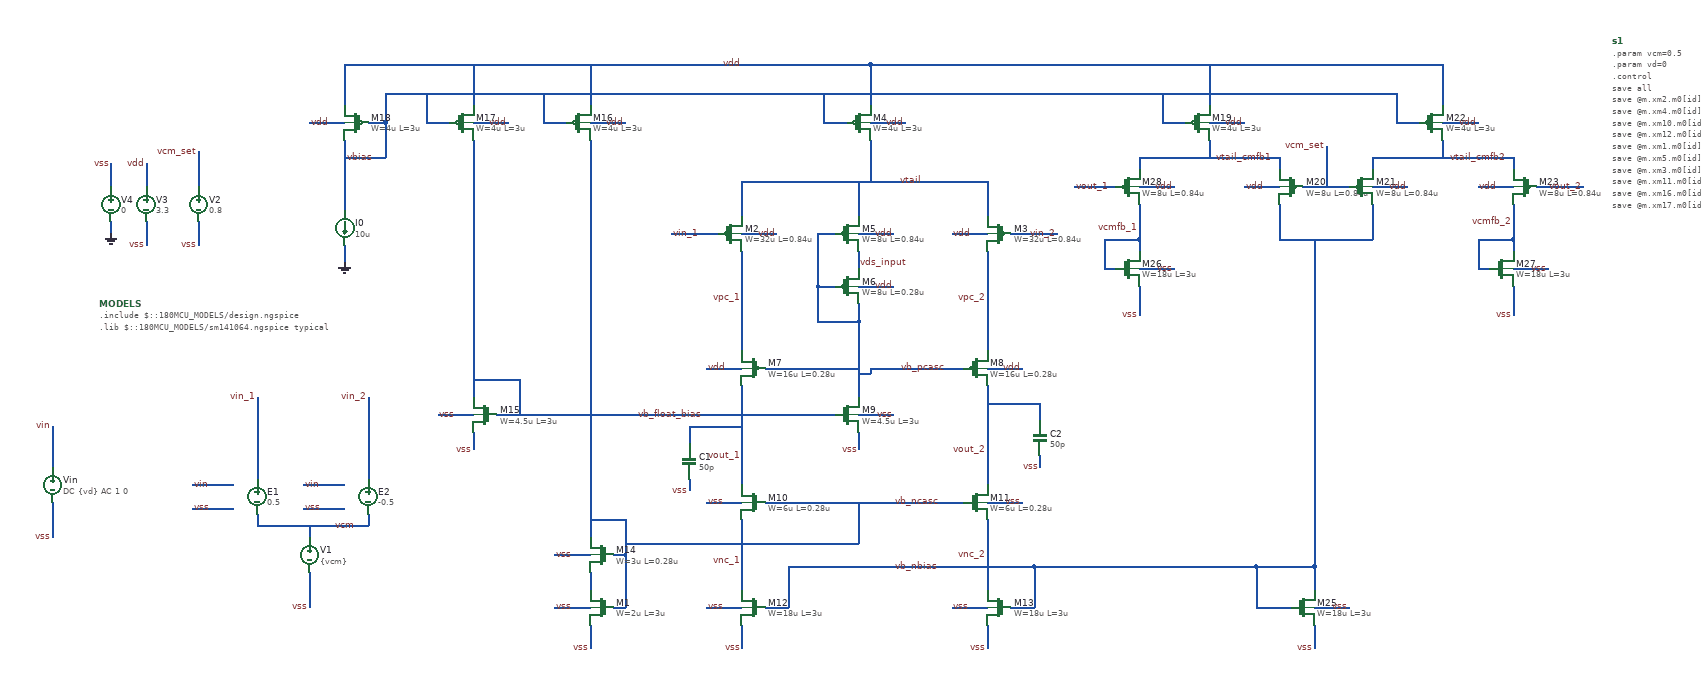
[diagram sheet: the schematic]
v {xschem version=3.4.8RC file_version=1.3}
G {}
K {}
V {}
S {}
F {}
E {}
N -100 -1020 -100 -950 {lab=vdd}
N -100 -1020 780 -1020 {lab=vdd}
N 320 -1020 320 -950 {lab=vdd}
N 120 -1020 120 -950 {lab=vdd}
N 580 -820 580 -760 {lab=vtail}
N 580 -820 1000 -820 {lab=vtail}
N 1000 -820 1000 -760 {lab=vtail}
N 780 -1020 800 -1020 {lab=vdd}
N 800 -1020 800 -950 {lab=vdd}
N 800 -890 800 -820 {lab=vtail}
N 780 -820 780 -760 {lab=vtail}
N 710 -730 740 -730 {lab=vb_pcasc}
N 710 -730 710 -640 {lab=vb_pcasc}
N 710 -640 740 -640 {lab=vb_pcasc}
N 710 -640 710 -580 {lab=vb_pcasc}
N 710 -580 780 -580 {lab=vb_pcasc}
N 780 -610 780 -580 {lab=vb_pcasc}
N 780 -700 780 -670 {lab=vds_input}
N 780 -580 780 -450 {lab=vb_pcasc}
N 620 -500 780 -500 {lab=vb_pcasc}
N 780 -490 800 -490 {lab=vb_pcasc}
N 800 -500 800 -490 {lab=vb_pcasc}
N 800 -500 960 -500 {lab=vb_pcasc}
N 780 -390 780 -360 {lab=vss}
N 120 -390 120 -360 {lab=vss}
N 160 -420 740 -420 {lab=vb_float_bias}
N 120 -890 120 -450 {lab=vb_float_bias}
N 200 -480 200 -420 {lab=vb_float_bias}
N 120 -480 200 -480 {lab=vb_float_bias}
N -100 -890 -100 -770 {lab=vbias}
N -60 -920 -30 -920 {lab=vbias}
N -30 -920 -30 -860 {lab=vbias}
N -100 -860 -30 -860 {lab=vbias}
N 320 -890 320 -210 {lab=vb_ncasc}
N 360 -90 380 -90 {lab=vb_ncasc}
N 380 -180 380 -90 {lab=vb_ncasc}
N 360 -180 380 -180 {lab=vb_ncasc}
N 380 -240 380 -180 {lab=vb_ncasc}
N 320 -240 380 -240 {lab=vb_ncasc}
N 320 -150 320 -120 {lab=#net1}
N 320 -60 320 -20 {lab=vss}
N 580 -700 580 -530 {lab=vpc_1}
N 580 -240 580 -120 {lab=vnc_1}
N 580 -470 580 -300 {lab=vout_1}
N 1000 -470 1000 -300 {lab=vout_2}
N 1000 -240 1000 -120 {lab=vnc_2}
N 620 -270 960 -270 {lab=vb_ncasc}
N 380 -200 780 -200 {lab=vb_ncasc}
N 780 -270 780 -200 {lab=vb_ncasc}
N 1000 -700 1000 -530 {lab=vpc_2}
N 580 -60 580 -20 {lab=vss}
N 1000 -60 1000 -20 {lab=vss}
N 1540 -810 1620 -810 {lab=vcm_set}
N 1660 -780 1660 -720 {lab=vb_nbias}
N 1500 -720 1660 -720 {lab=vb_nbias}
N 1500 -780 1500 -720 {lab=vb_nbias}
N 1460 -160 1460 -90 {lab=vb_nbias}
N 1460 -160 1560 -160 {lab=vb_nbias}
N 1560 -160 1560 -120 {lab=vb_nbias}
N 1560 -720 1560 -160 {lab=vb_nbias}
N 1500 -860 1500 -840 {lab=vtail_cmfb1}
N 1260 -860 1260 -840 {lab=vtail_cmfb1}
N 1260 -860 1490 -860 {lab=vtail_cmfb1}
N 1490 -860 1500 -860 {lab=vtail_cmfb1}
N 1380 -890 1380 -860 {lab=vtail_cmfb1}
N 800 -1020 1780 -1020 {lab=vdd}
N 1780 -1020 1780 -950 {lab=vdd}
N 1660 -860 1660 -840 {lab=vtail_cmfb2}
N 1660 -860 1900 -860 {lab=vtail_cmfb2}
N 1900 -860 1900 -840 {lab=vtail_cmfb2}
N 1780 -890 1780 -860 {lab=vtail_cmfb2}
N 1560 -60 1560 -20 {lab=vss}
N 1200 -670 1220 -670 {lab=vcmfb_1}
N 1200 -720 1200 -670 {lab=vcmfb_1}
N 1200 -720 1260 -720 {lab=vcmfb_1}
N 1260 -720 1260 -700 {lab=vcmfb_1}
N 1260 -780 1260 -720 {lab=vcmfb_1}
N 1260 -640 1260 -590 {lab=vss}
N 1840 -670 1860 -670 {lab=vcmfb_2}
N 1840 -720 1840 -670 {lab=vcmfb_2}
N 1840 -720 1900 -720 {lab=vcmfb_2}
N 1900 -720 1900 -700 {lab=vcmfb_2}
N 1900 -780 1900 -720 {lab=vcmfb_2}
N 1900 -640 1900 -590 {lab=vss}
N 460 -730 540 -730 {lab=vin_1}
N 1040 -730 1120 -730 {lab=vin_2}
N 1380 -1020 1380 -950 {lab=vdd}
N -30 -970 -30 -920 {lab=vbias}
N -30 -970 1700 -970 {lab=vbias}
N 1700 -920 1740 -920 {lab=vbias}
N 1700 -970 1700 -920 {lab=vbias}
N 1300 -920 1340 -920 {lab=vbias}
N 1300 -970 1300 -920 {lab=vbias}
N 720 -920 760 -920 {lab=vbias}
N 720 -970 720 -920 {lab=vbias}
N 240 -920 280 -920 {lab=vbias}
N 240 -970 240 -920 {lab=vbias}
N 40 -920 80 -920 {lab=vbias}
N 40 -970 40 -920 {lab=vbias}
N -100 -710 -100 -680 {lab=0}
N 1180 -810 1220 -810 {lab=vout_2}
N 1940 -810 1980 -810 {lab=vout_2}
N -160 -920 -100 -920 {lab=vdd}
N 120 -920 180 -920 {lab=vdd}
N 320 -920 380 -920 {lab=vdd}
N 800 -920 860 -920 {lab=vdd}
N 1380 -920 1440 -920 {lab=vdd}
N 1780 -920 1840 -920 {lab=vdd}
N 1660 -810 1720 -810 {lab=vdd}
N 1440 -810 1500 -810 {lab=vdd}
N 1260 -810 1320 -810 {lab=vdd}
N 1840 -810 1900 -810 {lab=vdd}
N 580 -730 640 -730 {lab=vdd}
N 940 -730 1000 -730 {lab=vdd}
N 780 -730 840 -730 {lab=vdd}
N 780 -640 840 -640 {lab=vdd}
N 520 -500 580 -500 {lab=vdd}
N 1000 -500 1060 -500 {lab=vdd}
N 780 -420 840 -420 {lab=vss}
N 520 -270 580 -270 {lab=vss}
N 1000 -270 1060 -270 {lab=vss}
N 940 -90 1000 -90 {lab=vss}
N 520 -90 580 -90 {lab=vss}
N 260 -90 320 -90 {lab=vss}
N 260 -180 320 -180 {lab=vss}
N 60 -420 120 -420 {lab=vss}
N 1460 -90 1520 -90 {lab=vb_nbias}
N 1080 -160 1460 -160 {lab=vb_nbias}
N 1080 -160 1080 -90 {lab=vb_nbias}
N 1040 -90 1080 -90 {lab=vb_nbias}
N 660 -160 1080 -160 {lab=vb_nbias}
N 660 -160 660 -90 {lab=vb_nbias}
N 620 -90 660 -90 {lab=vb_nbias}
N 1150 -810 1180 -810 {lab=vout_2}
N 1980 -810 2020 -810 {lab=vout_2}
N 1580 -880 1580 -810 {lab=vcm_set}
N -500 -750 -500 -730 {lab=0}
N -500 -850 -500 -820 {lab=vss}
N -500 -820 -500 -810 {lab=vss}
N -440 -750 -440 -730 {lab=vss}
N -440 -730 -440 -710 {lab=vss}
N -440 -850 -440 -810 {lab=vdd}
N -250 -250 -250 -230 {lab=vcm}
N -140 -230 -60 -230 {lab=vcm}
N -60 -250 -60 -230 {lab=vcm}
N -160 -230 -160 -210 {lab=vcm}
N -160 -150 -160 -90 {lab=vss}
N -250 -450 -250 -310 {lab=vin_1}
N -60 -360 -60 -310 {lab=vin_2}
N -250 -230 -140 -230 {lab=vcm}
N -360 -260 -290 -260 {lab=vss}
N -360 -300 -290 -300 {lab=vin}
N -170 -260 -100 -260 {lab=vss}
N -170 -300 -100 -300 {lab=vin}
N -600 -270 -600 -210 {lab=vss}
N -600 -400 -600 -330 {lab=vin}
N -60 -450 -60 -360 {lab=vin_2}
N -350 -750 -350 -730 {lab=vss}
N -350 -730 -350 -710 {lab=vss}
N -350 -850 -350 -810 {lab=vcm_set}
N -350 -870 -350 -850 {lab=vcm_set}
N 1260 -670 1320 -670 {lab=vss}
N 1900 -670 1960 -670 {lab=vss}
N 1560 -90 1620 -90 {lab=vss}
N 490 -400 490 -370 {lab=vout_1}
N 490 -400 580 -400 {lab=vout_1}
N 490 -310 490 -290 {lab=vss}
N 1090 -440 1090 -410 {lab=vout_2}
N 1000 -440 1090 -440 {lab=vout_2}
N 1090 -350 1090 -330 {lab=vss}
C {symbols/pfet_03v3.sym} 560 -730 0 0 {name=M2
L=0.84u
W=32u
nf=8
m=1
ad="'int((nf+1)/2) * W/nf * 0.18u'"
pd="'2*int((nf+1)/2) * (W/nf + 0.18u)'"
as="'int((nf+2)/2) * W/nf * 0.18u'"
ps="'2*int((nf+2)/2) * (W/nf + 0.18u)'"
nrd="'0.18u / W'" nrs="'0.18u / W'"
sa=0 sb=0 sd=0
model=pfet_03v3
spiceprefix=X
}
C {symbols/pfet_03v3.sym} 780 -920 0 0 {name=M4
L=3u
W=4u
nf=1
m=50
ad="'int((nf+1)/2) * W/nf * 0.18u'"
pd="'2*int((nf+1)/2) * (W/nf + 0.18u)'"
as="'int((nf+2)/2) * W/nf * 0.18u'"
ps="'2*int((nf+2)/2) * (W/nf + 0.18u)'"
nrd="'0.18u / W'" nrs="'0.18u / W'"
sa=0 sb=0 sd=0
model=pfet_03v3
spiceprefix=X
}
C {symbols/nfet_03v3.sym} 600 -270 0 1 {name=M10
L=0.28u
W=6u
nf=2
m=1
ad="'int((nf+1)/2) * W/nf * 0.18u'"
pd="'2*int((nf+1)/2) * (W/nf + 0.18u)'"
as="'int((nf+2)/2) * W/nf * 0.18u'"
ps="'2*int((nf+2)/2) * (W/nf + 0.18u)'"
nrd="'0.18u / W'" nrs="'0.18u / W'"
sa=0 sb=0 sd=0
model=nfet_03v3
spiceprefix=X
}
C {symbols/nfet_03v3.sym} 600 -90 0 1 {name=M12
L=3u
W=18u
nf=4
m=1
ad="'int((nf+1)/2) * W/nf * 0.18u'"
pd="'2*int((nf+1)/2) * (W/nf + 0.18u)'"
as="'int((nf+2)/2) * W/nf * 0.18u'"
ps="'2*int((nf+2)/2) * (W/nf + 0.18u)'"
nrd="'0.18u / W'" nrs="'0.18u / W'"
sa=0 sb=0 sd=0
model=nfet_03v3
spiceprefix=X
}
C {symbols/nfet_03v3.sym} 340 -90 0 1 {name=M1
L=3u
W=2u
nf=1
m=1
ad="'int((nf+1)/2) * W/nf * 0.18u'"
pd="'2*int((nf+1)/2) * (W/nf + 0.18u)'"
as="'int((nf+2)/2) * W/nf * 0.18u'"
ps="'2*int((nf+2)/2) * (W/nf + 0.18u)'"
nrd="'0.18u / W'" nrs="'0.18u / W'"
sa=0 sb=0 sd=0
model=nfet_03v3
spiceprefix=X
}
C {symbols/pfet_03v3.sym} 760 -730 0 0 {name=M5
L=0.84u
W=8u
nf=2
m=1
ad="'int((nf+1)/2) * W/nf * 0.18u'"
pd="'2*int((nf+1)/2) * (W/nf + 0.18u)'"
as="'int((nf+2)/2) * W/nf * 0.18u'"
ps="'2*int((nf+2)/2) * (W/nf + 0.18u)'"
nrd="'0.18u / W'" nrs="'0.18u / W'"
sa=0 sb=0 sd=0
model=pfet_03v3
spiceprefix=X
}
C {isource.sym} -100 -740 0 0 {name=I0 value=10u}
C {symbols/pfet_03v3.sym} 1020 -730 0 1 {name=M3
L=0.84u
W=32u
nf=8
m=1
ad="'int((nf+1)/2) * W/nf * 0.18u'"
pd="'2*int((nf+1)/2) * (W/nf + 0.18u)'"
as="'int((nf+2)/2) * W/nf * 0.18u'"
ps="'2*int((nf+2)/2) * (W/nf + 0.18u)'"
nrd="'0.18u / W'" nrs="'0.18u / W'"
sa=0 sb=0 sd=0
model=pfet_03v3
spiceprefix=X
}
C {symbols/nfet_03v3.sym} 980 -270 0 0 {name=M11
L=0.28u
W=6u
nf=2
m=1
ad="'int((nf+1)/2) * W/nf * 0.18u'"
pd="'2*int((nf+1)/2) * (W/nf + 0.18u)'"
as="'int((nf+2)/2) * W/nf * 0.18u'"
ps="'2*int((nf+2)/2) * (W/nf + 0.18u)'"
nrd="'0.18u / W'" nrs="'0.18u / W'"
sa=0 sb=0 sd=0
model=nfet_03v3
spiceprefix=X
}
C {symbols/pfet_03v3.sym} 300 -920 0 0 {name=M16
L=3u
W=4u
nf=1
m=10
ad="'int((nf+1)/2) * W/nf * 0.18u'"
pd="'2*int((nf+1)/2) * (W/nf + 0.18u)'"
as="'int((nf+2)/2) * W/nf * 0.18u'"
ps="'2*int((nf+2)/2) * (W/nf + 0.18u)'"
nrd="'0.18u / W'" nrs="'0.18u / W'"
sa=0 sb=0 sd=0
model=pfet_03v3
spiceprefix=X
}
C {symbols/pfet_03v3.sym} 100 -920 0 0 {name=M17
L=3u
W=4u
nf=1
m=10
ad="'int((nf+1)/2) * W/nf * 0.18u'"
pd="'2*int((nf+1)/2) * (W/nf + 0.18u)'"
as="'int((nf+2)/2) * W/nf * 0.18u'"
ps="'2*int((nf+2)/2) * (W/nf + 0.18u)'"
nrd="'0.18u / W'" nrs="'0.18u / W'"
sa=0 sb=0 sd=0
model=pfet_03v3
spiceprefix=X
}
C {symbols/pfet_03v3.sym} -80 -920 0 1 {name=M18
L=3u
W=4u
nf=1
m=10
ad="'int((nf+1)/2) * W/nf * 0.18u'"
pd="'2*int((nf+1)/2) * (W/nf + 0.18u)'"
as="'int((nf+2)/2) * W/nf * 0.18u'"
ps="'2*int((nf+2)/2) * (W/nf + 0.18u)'"
nrd="'0.18u / W'" nrs="'0.18u / W'"
sa=0 sb=0 sd=0
model=pfet_03v3
spiceprefix=X
}
C {symbols/nfet_03v3.sym} 1020 -90 0 1 {name=M13
L=3u
W=18u
nf=4
m=1
ad="'int((nf+1)/2) * W/nf * 0.18u'"
pd="'2*int((nf+1)/2) * (W/nf + 0.18u)'"
as="'int((nf+2)/2) * W/nf * 0.18u'"
ps="'2*int((nf+2)/2) * (W/nf + 0.18u)'"
nrd="'0.18u / W'" nrs="'0.18u / W'"
sa=0 sb=0 sd=0
model=nfet_03v3
spiceprefix=X
}
C {symbols/nfet_03v3.sym} 140 -420 0 1 {name=M15
L=3u
W=4.5u
nf=1
m=1
ad="'int((nf+1)/2) * W/nf * 0.18u'"
pd="'2*int((nf+1)/2) * (W/nf + 0.18u)'"
as="'int((nf+2)/2) * W/nf * 0.18u'"
ps="'2*int((nf+2)/2) * (W/nf + 0.18u)'"
nrd="'0.18u / W'" nrs="'0.18u / W'"
sa=0 sb=0 sd=0
model=nfet_03v3
spiceprefix=X
}
C {symbols/nfet_03v3.sym} 760 -420 0 0 {name=M9
L=3u
W=4.5u
nf=1
m=1
ad="'int((nf+1)/2) * W/nf * 0.18u'"
pd="'2*int((nf+1)/2) * (W/nf + 0.18u)'"
as="'int((nf+2)/2) * W/nf * 0.18u'"
ps="'2*int((nf+2)/2) * (W/nf + 0.18u)'"
nrd="'0.18u / W'" nrs="'0.18u / W'"
sa=0 sb=0 sd=0
model=nfet_03v3
spiceprefix=X
}
C {symbols/pfet_03v3.sym} 1360 -920 0 0 {name=M19
L=3u
W=4u
nf=1
m=20
ad="'int((nf+1)/2) * W/nf * 0.18u'"
pd="'2*int((nf+1)/2) * (W/nf + 0.18u)'"
as="'int((nf+2)/2) * W/nf * 0.18u'"
ps="'2*int((nf+2)/2) * (W/nf + 0.18u)'"
nrd="'0.18u / W'" nrs="'0.18u / W'"
sa=0 sb=0 sd=0
model=pfet_03v3
spiceprefix=X
}
C {symbols/pfet_03v3.sym} 1760 -920 0 0 {name=M22
L=3u
W=4u
nf=1
m=20
ad="'int((nf+1)/2) * W/nf * 0.18u'"
pd="'2*int((nf+1)/2) * (W/nf + 0.18u)'"
as="'int((nf+2)/2) * W/nf * 0.18u'"
ps="'2*int((nf+2)/2) * (W/nf + 0.18u)'"
nrd="'0.18u / W'" nrs="'0.18u / W'"
sa=0 sb=0 sd=0
model=pfet_03v3
spiceprefix=X
}
C {symbols/nfet_03v3.sym} 1540 -90 0 0 {name=M25
L=3u
W=18u
nf=4
m=1
ad="'int((nf+1)/2) * W/nf * 0.18u'"
pd="'2*int((nf+1)/2) * (W/nf + 0.18u)'"
as="'int((nf+2)/2) * W/nf * 0.18u'"
ps="'2*int((nf+2)/2) * (W/nf + 0.18u)'"
nrd="'0.18u / W'" nrs="'0.18u / W'"
sa=0 sb=0 sd=0
model=nfet_03v3
spiceprefix=X
}
C {symbols/nfet_03v3.sym} 1240 -670 0 0 {name=M26
L=3u
W=18u
nf=2
m=1
ad="'int((nf+1)/2) * W/nf * 0.18u'"
pd="'2*int((nf+1)/2) * (W/nf + 0.18u)'"
as="'int((nf+2)/2) * W/nf * 0.18u'"
ps="'2*int((nf+2)/2) * (W/nf + 0.18u)'"
nrd="'0.18u / W'" nrs="'0.18u / W'"
sa=0 sb=0 sd=0
model=nfet_03v3
spiceprefix=X
}
C {symbols/nfet_03v3.sym} 1880 -670 0 0 {name=M27
L=3u
W=18u
nf=2
m=1
ad="'int((nf+1)/2) * W/nf * 0.18u'"
pd="'2*int((nf+1)/2) * (W/nf + 0.18u)'"
as="'int((nf+2)/2) * W/nf * 0.18u'"
ps="'2*int((nf+2)/2) * (W/nf + 0.18u)'"
nrd="'0.18u / W'" nrs="'0.18u / W'"
sa=0 sb=0 sd=0
model=nfet_03v3
spiceprefix=X
}
C {symbols/pfet_03v3.sym} 1240 -810 0 0 {name=M28
L=0.84u
W=8u
nf=2
m=1
ad="'int((nf+1)/2) * W/nf * 0.18u'"
pd="'2*int((nf+1)/2) * (W/nf + 0.18u)'"
as="'int((nf+2)/2) * W/nf * 0.18u'"
ps="'2*int((nf+2)/2) * (W/nf + 0.18u)'"
nrd="'0.18u / W'" nrs="'0.18u / W'"
sa=0 sb=0 sd=0
model=pfet_03v3
spiceprefix=X
}
C {symbols/pfet_03v3.sym} 1520 -810 0 1 {name=M20
L=0.84u
W=8u
nf=2
m=1
ad="'int((nf+1)/2) * W/nf * 0.18u'"
pd="'2*int((nf+1)/2) * (W/nf + 0.18u)'"
as="'int((nf+2)/2) * W/nf * 0.18u'"
ps="'2*int((nf+2)/2) * (W/nf + 0.18u)'"
nrd="'0.18u / W'" nrs="'0.18u / W'"
sa=0 sb=0 sd=0
model=pfet_03v3
spiceprefix=X
}
C {symbols/pfet_03v3.sym} 1640 -810 0 0 {name=M21
L=0.84u
W=8u
nf=2
m=1
ad="'int((nf+1)/2) * W/nf * 0.18u'"
pd="'2*int((nf+1)/2) * (W/nf + 0.18u)'"
as="'int((nf+2)/2) * W/nf * 0.18u'"
ps="'2*int((nf+2)/2) * (W/nf + 0.18u)'"
nrd="'0.18u / W'" nrs="'0.18u / W'"
sa=0 sb=0 sd=0
model=pfet_03v3
spiceprefix=X
}
C {symbols/pfet_03v3.sym} 1920 -810 0 1 {name=M23
L=0.84u
W=8u
nf=2
m=1
ad="'int((nf+1)/2) * W/nf * 0.18u'"
pd="'2*int((nf+1)/2) * (W/nf + 0.18u)'"
as="'int((nf+2)/2) * W/nf * 0.18u'"
ps="'2*int((nf+2)/2) * (W/nf + 0.18u)'"
nrd="'0.18u / W'" nrs="'0.18u / W'"
sa=0 sb=0 sd=0
model=pfet_03v3
spiceprefix=X
}
C {lab_wire.sym} -160 -920 0 1 {name=p1 sig_type=std_logic lab=vdd}
C {lab_wire.sym} 180 -920 0 0 {name=p2 sig_type=std_logic lab=vdd}
C {lab_wire.sym} 380 -920 0 0 {name=p3 sig_type=std_logic lab=vdd}
C {lab_wire.sym} 860 -920 0 0 {name=p4 sig_type=std_logic lab=vdd}
C {lab_wire.sym} 1440 -920 0 0 {name=p5 sig_type=std_logic lab=vdd}
C {lab_wire.sym} 1840 -920 0 0 {name=p6 sig_type=std_logic lab=vdd}
C {lab_wire.sym} 1720 -810 0 0 {name=p7 sig_type=std_logic lab=vdd}
C {lab_wire.sym} 1440 -810 0 1 {name=p8 sig_type=std_logic lab=vdd}
C {lab_wire.sym} 1320 -810 0 0 {name=p9 sig_type=std_logic lab=vdd}
C {lab_wire.sym} 1840 -810 0 1 {name=p10 sig_type=std_logic lab=vdd}
C {lab_wire.sym} 640 -730 0 0 {name=p11 sig_type=std_logic lab=vdd}
C {lab_wire.sym} 940 -730 0 1 {name=p12 sig_type=std_logic lab=vdd}
C {lab_wire.sym} 840 -730 0 0 {name=p13 sig_type=std_logic lab=vdd}
C {lab_wire.sym} 840 -640 0 0 {name=p14 sig_type=std_logic lab=vdd}
C {symbols/pfet_03v3.sym} 760 -640 0 0 {name=M6
L=0.28u
W=8u
nf=2
m=1
ad="'int((nf+1)/2) * W/nf * 0.18u'"
pd="'2*int((nf+1)/2) * (W/nf + 0.18u)'"
as="'int((nf+2)/2) * W/nf * 0.18u'"
ps="'2*int((nf+2)/2) * (W/nf + 0.18u)'"
nrd="'0.18u / W'" nrs="'0.18u / W'"
sa=0 sb=0 sd=0
model=pfet_03v3
spiceprefix=X
}
C {symbols/pfet_03v3.sym} 600 -500 0 1 {name=M7
L=0.28u
W=16u
nf=4
m=1
ad="'int((nf+1)/2) * W/nf * 0.18u'"
pd="'2*int((nf+1)/2) * (W/nf + 0.18u)'"
as="'int((nf+2)/2) * W/nf * 0.18u'"
ps="'2*int((nf+2)/2) * (W/nf + 0.18u)'"
nrd="'0.18u / W'" nrs="'0.18u / W'"
sa=0 sb=0 sd=0
model=pfet_03v3
spiceprefix=X
}
C {symbols/pfet_03v3.sym} 980 -500 0 0 {name=M8
L=0.28u
W=16u
nf=4
m=1
ad="'int((nf+1)/2) * W/nf * 0.18u'"
pd="'2*int((nf+1)/2) * (W/nf + 0.18u)'"
as="'int((nf+2)/2) * W/nf * 0.18u'"
ps="'2*int((nf+2)/2) * (W/nf + 0.18u)'"
nrd="'0.18u / W'" nrs="'0.18u / W'"
sa=0 sb=0 sd=0
model=pfet_03v3
spiceprefix=X
}
C {lab_wire.sym} 520 -500 0 1 {name=p15 sig_type=std_logic lab=vdd}
C {lab_wire.sym} 1060 -500 0 0 {name=p16 sig_type=std_logic lab=vdd}
C {lab_wire.sym} 840 -420 0 0 {name=p17 sig_type=std_logic lab=vss}
C {lab_wire.sym} 520 -270 0 1 {name=p18 sig_type=std_logic lab=vss}
C {lab_wire.sym} 1060 -270 0 0 {name=p19 sig_type=std_logic lab=vss}
C {lab_wire.sym} 940 -90 0 1 {name=p20 sig_type=std_logic lab=vss}
C {lab_wire.sym} 520 -90 0 1 {name=p21 sig_type=std_logic lab=vss}
C {lab_wire.sym} 260 -90 0 1 {name=p22 sig_type=std_logic lab=vss}
C {lab_wire.sym} 260 -180 0 1 {name=p23 sig_type=std_logic lab=vss}
C {lab_wire.sym} 60 -420 0 1 {name=p24 sig_type=std_logic lab=vss}
C {lab_wire.sym} 320 -20 3 1 {name=p25 sig_type=std_logic lab=vss}
C {lab_wire.sym} 580 -20 3 1 {name=p26 sig_type=std_logic lab=vss}
C {lab_wire.sym} 1000 -20 3 1 {name=p27 sig_type=std_logic lab=vss}
C {lab_wire.sym} 780 -360 3 1 {name=p28 sig_type=std_logic lab=vss}
C {lab_wire.sym} 120 -360 1 0 {name=p29 sig_type=std_logic lab=vss}
C {lab_wire.sym} 1560 -20 3 1 {name=p30 sig_type=std_logic lab=vss}
C {lab_wire.sym} 1260 -590 3 1 {name=p31 sig_type=std_logic lab=vss}
C {lab_wire.sym} 1900 -590 3 1 {name=p32 sig_type=std_logic lab=vss}
C {lab_wire.sym} 580 -1020 0 0 {name=p33 sig_type=std_logic lab=vdd}
C {symbols/nfet_03v3.sym} 340 -180 0 1 {name=M14
L=0.28u
W=3u
nf=1
m=1
ad="'int((nf+1)/2) * W/nf * 0.18u'"
pd="'2*int((nf+1)/2) * (W/nf + 0.18u)'"
as="'int((nf+2)/2) * W/nf * 0.18u'"
ps="'2*int((nf+2)/2) * (W/nf + 0.18u)'"
nrd="'0.18u / W'" nrs="'0.18u / W'"
sa=0 sb=0 sd=0
model=nfet_03v3
spiceprefix=X
}
C {lab_wire.sym} 460 -730 0 1 {name=p35 sig_type=std_logic lab=vin_1}
C {lab_wire.sym} 1120 -730 0 0 {name=p36 sig_type=std_logic lab=vin_2}
C {lab_wire.sym} 890 -820 0 0 {name=p37 sig_type=std_logic lab=vtail}
C {lab_wire.sym} 580 -620 1 0 {name=p38 sig_type=std_logic lab=vpc_1}
C {lab_wire.sym} 1000 -620 1 0 {name=p39 sig_type=std_logic lab=vpc_2}
C {lab_wire.sym} 850 -500 0 1 {name=p40 sig_type=std_logic lab=vb_pcasc}
C {lab_wire.sym} 840 -270 0 1 {name=p41 sig_type=std_logic lab=vb_ncasc}
C {lab_wire.sym} 840 -160 0 1 {name=p42 sig_type=std_logic lab=vb_nbias}
C {lab_wire.sym} 780 -680 0 1 {name=p43 sig_type=std_logic lab=vds_input}
C {lab_wire.sym} 400 -420 0 1 {name=p44 sig_type=std_logic lab=vb_float_bias}
C {lab_wire.sym} 580 -350 3 1 {name=p45 sig_type=std_logic lab=vout_1}
C {lab_wire.sym} 1000 -360 1 0 {name=p46 sig_type=std_logic lab=vout_2}
C {lab_wire.sym} 1150 -810 0 1 {name=p47 sig_type=std_logic lab=vout_1}
C {lab_wire.sym} 2020 -810 0 0 {name=p48 sig_type=std_logic lab=vout_2}
C {lab_wire.sym} 1490 -860 0 0 {name=p49 sig_type=std_logic lab=vtail_cmfb1}
C {lab_wire.sym} 1890 -860 0 0 {name=p50 sig_type=std_logic lab=vtail_cmfb2}
C {lab_wire.sym} 1580 -880 1 1 {name=p51 sig_type=std_logic lab=vcm_set}
C {lab_wire.sym} 1260 -740 0 0 {name=p52 sig_type=std_logic lab=vcmfb_1}
C {lab_wire.sym} 1900 -750 0 0 {name=p53 sig_type=std_logic lab=vcmfb_2}
C {lab_wire.sym} -50 -860 0 0 {name=p54 sig_type=std_logic lab=vbias}
C {vsource.sym} -440 -780 0 0 {name=V3 value=3.3 savecurrent=false}
C {vsource.sym} -500 -780 0 0 {name=V4 value=0 savecurrent=false}
C {gnd.sym} -500 -730 0 0 {name=l2 lab=0}
C {lab_wire.sym} -500 -850 3 0 {name=p55 sig_type=std_logic lab=vss}
C {lab_wire.sym} -440 -710 3 1 {name=p56 sig_type=std_logic lab=vss}
C {lab_wire.sym} -440 -850 3 0 {name=p57 sig_type=std_logic lab=vdd}
C {vsource.sym} -160 -180 0 0 {name=V1 value=\{vcm\} savecurrent=false}
C {lab_wire.sym} -160 -90 3 1 {name=p58 sig_type=std_logic lab=vss}
C {lab_wire.sym} -80 -230 0 0 {name=p59 sig_type=std_logic lab=vcm}
C {devices/code_shown.sym} -520 -610 0 0 {name=MODELS only_toplevel=true
format="tcleval( @value )"
value="
.include $::180MCU_MODELS/design.ngspice
.lib $::180MCU_MODELS/sm141064.ngspice typical
"}
C {vcvs.sym} -250 -280 0 0 {name=E1 value=0.5}
C {vcvs.sym} -60 -280 0 0 {name=E2 value=-0.5}
C {lab_wire.sym} -360 -260 0 1 {name=p60 sig_type=std_logic lab=vss}
C {lab_wire.sym} -360 -300 0 1 {name=p61 sig_type=std_logic lab=vin}
C {lab_wire.sym} -170 -260 0 1 {name=p62 sig_type=std_logic lab=vss}
C {lab_wire.sym} -170 -300 0 1 {name=p63 sig_type=std_logic lab=vin}
C {vsource.sym} -600 -300 0 0 {name=Vin value="DC \{vd\} AC 1 0" savecurrent=false}
C {lab_wire.sym} -600 -210 3 1 {name=p64 sig_type=std_logic lab=vss}
C {lab_wire.sym} -600 -400 3 0 {name=p65 sig_type=std_logic lab=vin}
C {lab_wire.sym} -250 -450 1 1 {name=p66 sig_type=std_logic lab=vin_1}
C {lab_wire.sym} -60 -450 1 1 {name=p67 sig_type=std_logic lab=vin_2}
C {vsource.sym} -350 -780 0 0 {name=V2 value=0.8 savecurrent=false}
C {lab_wire.sym} -350 -710 3 1 {name=p68 sig_type=std_logic lab=vss}
C {lab_wire.sym} -350 -870 3 0 {name=p69 sig_type=std_logic lab=vcm_set}
C {code_shown.sym} 2070 -1060 0 0 {name=s1 only_toplevel=false value=".param vcm=0.5
.param vd=0
.control
save all
save @m.xm2.m0[id] @m.xm2.m0[gm] @m.xm2.m0[gds] @m.xm2.m0[cdb] @m.xm2.m0[cgs] @m.xm2.m0[csb] @m.xm2.m0[cgd]
save @m.xm4.m0[id] @m.xm4.m0[gm] @m.xm4.m0[gds] @m.xm4.m0[cdb] @m.xm4.m0[cgs] @m.xm4.m0[csb] @m.xm4.m0[cgd]
save @m.xm10.m0[id] @m.xm10.m0[gm] @m.xm10.m0[gds] @m.xm10.m0[cdb] @m.xm10.m0[cgs] @m.xm10.m0[csb] @m.xm10.m0[cgd]
save @m.xm12.m0[id] @m.xm12.m0[gm] @m.xm12.m0[gds] @m.xm12.m0[cdb] @m.xm12.m0[cgs] @m.xm12.m0[csb] @m.xm12.m0[cgd]
save @m.xm1.m0[id] @m.xm1.m0[gm] @m.xm1.m0[gds] @m.xm1.m0[cdb] @m.xm1.m0[cgs] @m.xm1.m0[csb] @m.xm1.m0[cgd]
save @m.xm5.m0[id] @m.xm5.m0[gm] @m.xm5.m0[gds] @m.xm5.m0[cdb] @m.xm5.m0[cgs] @m.xm5.m0[csb] @m.xm5.m0[cgd]
save @m.xm3.m0[id] @m.xm3.m0[gm] @m.xm3.m0[gds] @m.xm3.m0[cdb] @m.xm3.m0[cgs] @m.xm3.m0[csb] @m.xm3.m0[cgd]
save @m.xm11.m0[id] @m.xm11.m0[gm] @m.xm11.m0[gds] @m.xm11.m0[cdb] @m.xm11.m0[cgs] @m.xm11.m0[csb] @m.xm11.m0[cgd]
save @m.xm16.m0[id] @m.xm16.m0[gm] @m.xm16.m0[gds] @m.xm16.m0[cdb] @m.xm16.m0[cgs] @m.xm16.m0[csb] @m.xm16.m0[cgd]
save @m.xm17.m0[id] @m.xm17.m0[gm] @m.xm17.m0[gds] @m.xm17.m0[cdb] @m.xm17.m0[cgs] @m.xm17.m0[csb] @m.xm17.m0[cgd]
save @m.xm18.m0[id] @m.xm18.m0[gm] @m.xm18.m0[gds] @m.xm18.m0[cdb] @m.xm18.m0[cgs] @m.xm18.m0[csb] @m.xm18.m0[cgd]
save @m.xm13.m0[id] @m.xm13.m0[gm] @m.xm13.m0[gds] @m.xm13.m0[cdb] @m.xm13.m0[cgs] @m.xm13.m0[csb] @m.xm13.m0[cgd]
save @m.xm15.m0[id] @m.xm15.m0[gm] @m.xm15.m0[gds] @m.xm15.m0[cdb] @m.xm15.m0[cgs] @m.xm15.m0[csb] @m.xm15.m0[cgd]
save @m.xm9.m0[id] @m.xm9.m0[gm] @m.xm9.m0[gds] @m.xm9.m0[cdb] @m.xm9.m0[cgs] @m.xm9.m0[csb] @m.xm9.m0[cgd]
save @m.xm19.m0[id] @m.xm19.m0[gm] @m.xm19.m0[gds] @m.xm19.m0[cdb] @m.xm19.m0[cgs] @m.xm19.m0[csb] @m.xm19.m0[cgd]
save @m.xm22.m0[id] @m.xm22.m0[gm] @m.xm22.m0[gds] @m.xm22.m0[cdb] @m.xm22.m0[cgs] @m.xm22.m0[csb] @m.xm22.m0[cgd]
save @m.xm25.m0[id] @m.xm25.m0[gm] @m.xm25.m0[gds] @m.xm25.m0[cdb] @m.xm25.m0[cgs] @m.xm25.m0[csb] @m.xm25.m0[cgd]
save @m.xm26.m0[id] @m.xm26.m0[gm] @m.xm26.m0[gds] @m.xm26.m0[cdb] @m.xm26.m0[cgs] @m.xm26.m0[csb] @m.xm26.m0[cgd]
save @m.xm27.m0[id] @m.xm27.m0[gm] @m.xm27.m0[gds] @m.xm27.m0[cdb] @m.xm27.m0[cgs] @m.xm27.m0[csb] @m.xm27.m0[cgd]
save @m.xm28.m0[id] @m.xm28.m0[gm] @m.xm28.m0[gds] @m.xm28.m0[cdb] @m.xm28.m0[cgs] @m.xm28.m0[csb] @m.xm28.m0[cgd]
save @m.xm20.m0[id] @m.xm20.m0[gm] @m.xm20.m0[gds] @m.xm20.m0[cdb] @m.xm20.m0[cgs] @m.xm20.m0[csb] @m.xm20.m0[cgd]
save @m.xm21.m0[id] @m.xm21.m0[gm] @m.xm21.m0[gds] @m.xm21.m0[cdb] @m.xm21.m0[cgs] @m.xm21.m0[csb] @m.xm21.m0[cgd]
save @m.xm23.m0[id] @m.xm23.m0[gm] @m.xm23.m0[gds] @m.xm23.m0[cdb] @m.xm23.m0[cgs] @m.xm23.m0[csb] @m.xm23.m0[cgd]
save @m.xm6.m0[id] @m.xm6.m0[gm] @m.xm6.m0[gds] @m.xm6.m0[cdb] @m.xm6.m0[cgs] @m.xm6.m0[csb] @m.xm6.m0[cgd]
save @m.xm7.m0[id] @m.xm7.m0[gm] @m.xm7.m0[gds] @m.xm7.m0[cdb] @m.xm7.m0[cgs] @m.xm7.m0[csb] @m.xm7.m0[cgd]
save @m.xm8.m0[id] @m.xm8.m0[gm] @m.xm8.m0[gds] @m.xm8.m0[cdb] @m.xm8.m0[cgs] @m.xm8.m0[csb] @m.xm8.m0[cgd]
save @m.xm14.m0[id] @m.xm14.m0[gm] @m.xm14.m0[gds] @m.xm14.m0[cdb] @m.xm14.m0[cgs] @m.xm14.m0[csb] @m.xm14.m0[cgd]
op
write results_op.raw all
ac dec 100 1 10G
.endc"}
C {lab_wire.sym} 1320 -670 0 0 {name=p70 sig_type=std_logic lab=vss}
C {lab_wire.sym} 1960 -670 0 0 {name=p71 sig_type=std_logic lab=vss}
C {lab_wire.sym} 1620 -90 0 0 {name=p72 sig_type=std_logic lab=vss}
C {gnd.sym} -100 -680 0 0 {name=l1 lab=0}
C {lab_wire.sym} 580 -170 1 0 {name=p34 sig_type=std_logic lab=vnc_1}
C {lab_wire.sym} 1000 -180 1 0 {name=p73 sig_type=std_logic lab=vnc_2}
C {capa.sym} 490 -340 0 0 {name=C1
m=1
value=50p
footprint=1206
device="ceramic capacitor"}
C {lab_wire.sym} 490 -290 3 1 {name=p74 sig_type=std_logic lab=vss}
C {capa.sym} 1090 -380 0 1 {name=C2
m=1
value=50p
footprint=1206
device="ceramic capacitor"}
C {lab_wire.sym} 1090 -330 1 0 {name=p75 sig_type=std_logic lab=vss}
